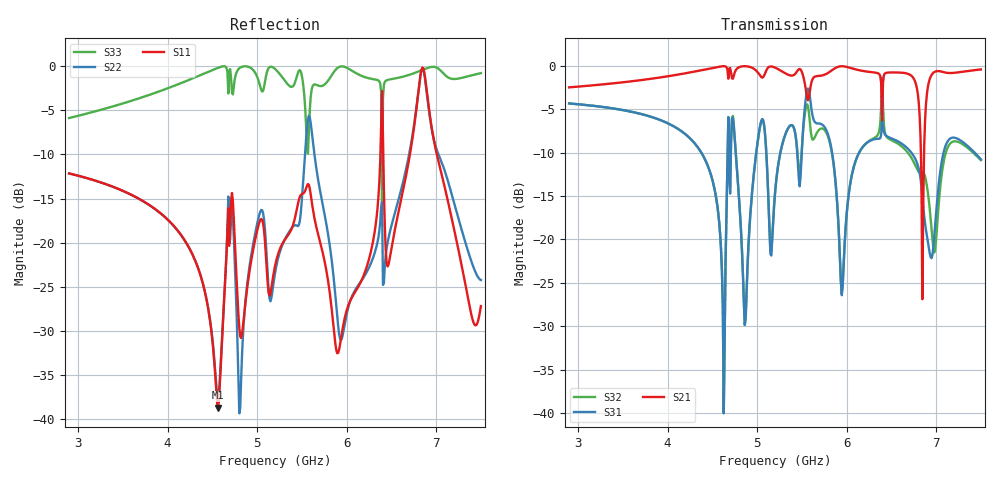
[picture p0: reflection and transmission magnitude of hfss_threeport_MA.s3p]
! Touchstone file from project Project1
! Exported from HFSS 2017.1.0
!Data is not renormalized
# GHZ S MA
! Modal data exported
! Port[1] = 1:1
! Port[2] = 2:1
! Port[3] = 3:1
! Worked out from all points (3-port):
!   451 points, 2.9 GHz to 7.5 GHz, reference per port
!   strongest paths, dB at 2.9 GHz, 4.045 GHz, 5.2 GHz, 6.355 GHz, 7.5 GHz:
!     S21: -2.5, -1.1, -0.2, -0.9, -0.4
!     S31: -4.3, -6.8, -14.7, -8.4, -10.8
!     S32: -4.3, -6.8, -14.6, -7.8, -10.9
!   lowest |S11| = -38.7 dB at 4.566 GHz (marker M1), VSWR 1.02
!   |S11| at or under -10 dB: start of sweep to 6.378 GHz; 6.41 GHz to 6.707 GHz (297.7 MHz wide, 4.54 % of centre); 7.008 GHz to end of sweep
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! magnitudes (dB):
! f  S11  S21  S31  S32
! 2.9 GHz  -12.2  -2.5  -4.3  -4.3
! 4.566 GHz  -38.7  -0.1  -17.0  -17.0
! 4.628 GHz  -27.1  0.0  -40.0  -40.1
! 4.72 GHz  -14.4  -1.4  -6.2  -5.9
! 4.812 GHz  -30.6  -0.1  -17.5  -17.3
! 5.2 GHz  -22.7  -0.2  -14.7  -14.6
! 5.588 GHz  -13.9  -3.0  -3.4  -6.4
! 5.905 GHz  -32.5  -0.1  -17.6  -17.7
! 6.846 GHz  -0.2  -26.9  -14.9  -12.2
! 7.5 GHz  -27.2  -0.4  -10.8  -10.9
